VERSION 5.8 ;
BUSBITCHARS "[]" ;
DIVIDERCHAR "/" ;

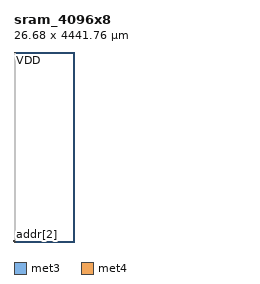
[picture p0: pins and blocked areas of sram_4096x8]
MACRO sram_4096x8
  CLASS BLOCK ;
  ORIGIN 0 0 ;
  SIZE 26.680 BY 4441.760 ;
  SYMMETRY X Y ;

  PIN clk
    DIRECTION INPUT ;
    USE CLOCK ;
    PORT
      LAYER met3 ;
        RECT -0.500 3.000 0.500 3.280 ;
    END
  END clk

  PIN ce
    DIRECTION INPUT ;
    USE SIGNAL ;
    PORT
      LAYER met3 ;
        RECT -0.500 4.000 0.500 4.280 ;
    END
  END ce

  PIN we
    DIRECTION INPUT ;
    USE SIGNAL ;
    PORT
      LAYER met3 ;
        RECT -0.500 5.000 0.500 5.280 ;
    END
  END we

  PIN addr[0]
    DIRECTION INPUT ;
    USE SIGNAL ;
    PORT
      LAYER met3 ;
        RECT -0.500 6.000 0.500 6.280 ;
    END
  END addr[0]

  PIN addr[1]
    DIRECTION INPUT ;
    USE SIGNAL ;
    PORT
      LAYER met3 ;
        RECT -0.500 7.000 0.500 7.280 ;
    END
  END addr[1]

  PIN addr[2]
    DIRECTION INPUT ;
    USE SIGNAL ;
    PORT
      LAYER met3 ;
        RECT -0.500 8.000 0.500 8.280 ;
    END
  END addr[2]

  PIN addr[3]
    DIRECTION INPUT ;
    USE SIGNAL ;
    PORT
      LAYER met3 ;
        RECT -0.500 9.000 0.500 9.280 ;
    END
  END addr[3]

  PIN addr[4]
    DIRECTION INPUT ;
    USE SIGNAL ;
    PORT
      LAYER met3 ;
        RECT -0.500 10.000 0.500 10.280 ;
    END
  END addr[4]

  PIN addr[5]
    DIRECTION INPUT ;
    USE SIGNAL ;
    PORT
      LAYER met3 ;
        RECT -0.500 11.000 0.500 11.280 ;
    END
  END addr[5]

  PIN addr[6]
    DIRECTION INPUT ;
    USE SIGNAL ;
    PORT
      LAYER met3 ;
        RECT -0.500 12.000 0.500 12.280 ;
    END
  END addr[6]

  PIN addr[7]
    DIRECTION INPUT ;
    USE SIGNAL ;
    PORT
      LAYER met3 ;
        RECT -0.500 13.000 0.500 13.280 ;
    END
  END addr[7]

  PIN addr[8]
    DIRECTION INPUT ;
    USE SIGNAL ;
    PORT
      LAYER met3 ;
        RECT -0.500 14.000 0.500 14.280 ;
    END
  END addr[8]

  PIN addr[9]
    DIRECTION INPUT ;
    USE SIGNAL ;
    PORT
      LAYER met3 ;
        RECT -0.500 15.000 0.500 15.280 ;
    END
  END addr[9]

  PIN addr[10]
    DIRECTION INPUT ;
    USE SIGNAL ;
    PORT
      LAYER met3 ;
        RECT -0.500 16.000 0.500 16.280 ;
    END
  END addr[10]

  PIN addr[11]
    DIRECTION INPUT ;
    USE SIGNAL ;
    PORT
      LAYER met3 ;
        RECT -0.500 17.000 0.500 17.280 ;
    END
  END addr[11]

  PIN din[0]
    DIRECTION INPUT ;
    USE SIGNAL ;
    PORT
      LAYER met3 ;
        RECT -0.500 18.000 0.500 18.280 ;
    END
  END din[0]

  PIN din[1]
    DIRECTION INPUT ;
    USE SIGNAL ;
    PORT
      LAYER met3 ;
        RECT -0.500 19.000 0.500 19.280 ;
    END
  END din[1]

  PIN din[2]
    DIRECTION INPUT ;
    USE SIGNAL ;
    PORT
      LAYER met3 ;
        RECT -0.500 20.000 0.500 20.280 ;
    END
  END din[2]

  PIN din[3]
    DIRECTION INPUT ;
    USE SIGNAL ;
    PORT
      LAYER met3 ;
        RECT -0.500 21.000 0.500 21.280 ;
    END
  END din[3]

  PIN din[4]
    DIRECTION INPUT ;
    USE SIGNAL ;
    PORT
      LAYER met3 ;
        RECT -0.500 22.000 0.500 22.280 ;
    END
  END din[4]

  PIN din[5]
    DIRECTION INPUT ;
    USE SIGNAL ;
    PORT
      LAYER met3 ;
        RECT -0.500 23.000 0.500 23.280 ;
    END
  END din[5]

  PIN din[6]
    DIRECTION INPUT ;
    USE SIGNAL ;
    PORT
      LAYER met3 ;
        RECT -0.500 24.000 0.500 24.280 ;
    END
  END din[6]

  PIN din[7]
    DIRECTION INPUT ;
    USE SIGNAL ;
    PORT
      LAYER met3 ;
        RECT -0.500 25.000 0.500 25.280 ;
    END
  END din[7]

  PIN dout[0]
    DIRECTION OUTPUT ;
    USE SIGNAL ;
    PORT
      LAYER met3 ;
        RECT 26.180 3.000 27.180 3.280 ;
    END
  END dout[0]

  PIN dout[1]
    DIRECTION OUTPUT ;
    USE SIGNAL ;
    PORT
      LAYER met3 ;
        RECT 26.180 4.000 27.180 4.280 ;
    END
  END dout[1]

  PIN dout[2]
    DIRECTION OUTPUT ;
    USE SIGNAL ;
    PORT
      LAYER met3 ;
        RECT 26.180 5.000 27.180 5.280 ;
    END
  END dout[2]

  PIN dout[3]
    DIRECTION OUTPUT ;
    USE SIGNAL ;
    PORT
      LAYER met3 ;
        RECT 26.180 6.000 27.180 6.280 ;
    END
  END dout[3]

  PIN dout[4]
    DIRECTION OUTPUT ;
    USE SIGNAL ;
    PORT
      LAYER met3 ;
        RECT 26.180 7.000 27.180 7.280 ;
    END
  END dout[4]

  PIN dout[5]
    DIRECTION OUTPUT ;
    USE SIGNAL ;
    PORT
      LAYER met3 ;
        RECT 26.180 8.000 27.180 8.280 ;
    END
  END dout[5]

  PIN dout[6]
    DIRECTION OUTPUT ;
    USE SIGNAL ;
    PORT
      LAYER met3 ;
        RECT 26.180 9.000 27.180 9.280 ;
    END
  END dout[6]

  PIN dout[7]
    DIRECTION OUTPUT ;
    USE SIGNAL ;
    PORT
      LAYER met3 ;
        RECT 26.180 10.000 27.180 10.280 ;
    END
  END dout[7]

  PIN VDD
    DIRECTION INOUT ;
    USE POWER ;
    PORT
      LAYER met4 ;
        RECT 0.000 4440.760 26.680 4441.760 ;
    END
  END VDD

  PIN VSS
    DIRECTION INOUT ;
    USE GROUND ;
    PORT
      LAYER met4 ;
        RECT 0.000 0.000 26.680 1.000 ;
    END
  END VSS

  OBS
    LAYER met1 ;
      RECT 2.000 2.000 24.680 4439.760 ;
    LAYER met2 ;
      RECT 2.000 2.000 24.680 4439.760 ;
  END

END sram_4096x8

END LIBRARY
